VERSION 5.7 ;
  NOWIREEXTENSIONATPIN ON ;
  DIVIDERCHAR "/" ;
  BUSBITCHARS "[]" ;
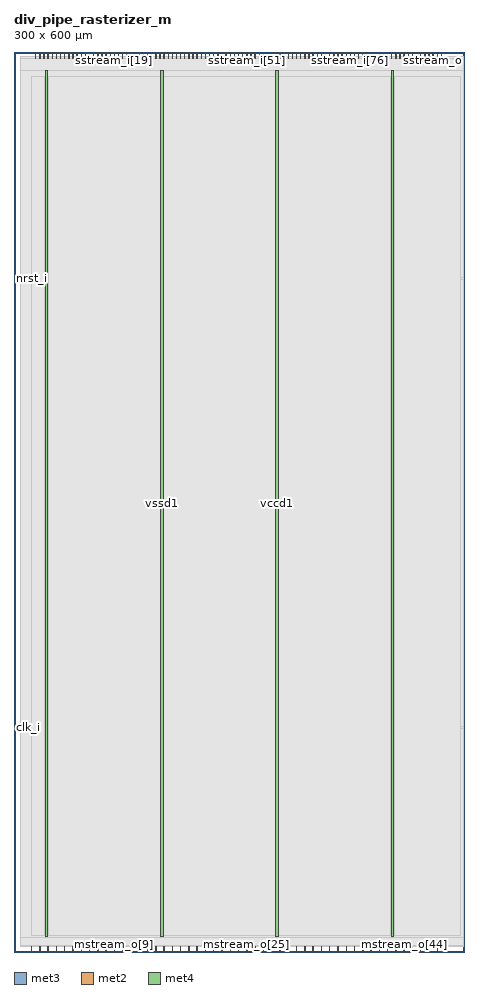
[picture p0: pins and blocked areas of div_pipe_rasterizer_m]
MACRO div_pipe_rasterizer_m
  CLASS BLOCK ;
  FOREIGN div_pipe_rasterizer_m ;
  ORIGIN 0.000 0.000 ;
  SIZE 300.000 BY 600.000 ;
  PIN clk_i
    DIRECTION INPUT ;
    USE SIGNAL ;
    ANTENNAGATEAREA 0.852000 ;
    PORT
      LAYER met3 ;
        RECT 0.000 149.640 4.000 150.240 ;
    END
  END clk_i
  PIN mstream_i
    DIRECTION INPUT ;
    USE SIGNAL ;
    ANTENNAGATEAREA 0.247500 ;
    PORT
      LAYER met2 ;
        RECT 11.590 0.000 11.870 4.000 ;
    END
  END mstream_i
  PIN mstream_o[0]
    DIRECTION OUTPUT TRISTATE ;
    USE SIGNAL ;
    ANTENNADIFFAREA 2.673000 ;
    PORT
      LAYER met2 ;
        RECT 17.110 0.000 17.390 4.000 ;
    END
  END mstream_o[0]
  PIN mstream_o[10]
    DIRECTION OUTPUT TRISTATE ;
    USE SIGNAL ;
    ANTENNADIFFAREA 2.673000 ;
    PORT
      LAYER met2 ;
        RECT 72.310 0.000 72.590 4.000 ;
    END
  END mstream_o[10]
  PIN mstream_o[11]
    DIRECTION OUTPUT TRISTATE ;
    USE SIGNAL ;
    ANTENNADIFFAREA 2.673000 ;
    PORT
      LAYER met2 ;
        RECT 77.830 0.000 78.110 4.000 ;
    END
  END mstream_o[11]
  PIN mstream_o[12]
    DIRECTION OUTPUT TRISTATE ;
    USE SIGNAL ;
    ANTENNADIFFAREA 2.673000 ;
    PORT
      LAYER met2 ;
        RECT 83.350 0.000 83.630 4.000 ;
    END
  END mstream_o[12]
  PIN mstream_o[13]
    DIRECTION OUTPUT TRISTATE ;
    USE SIGNAL ;
    ANTENNADIFFAREA 2.673000 ;
    PORT
      LAYER met2 ;
        RECT 88.870 0.000 89.150 4.000 ;
    END
  END mstream_o[13]
  PIN mstream_o[14]
    DIRECTION OUTPUT TRISTATE ;
    USE SIGNAL ;
    ANTENNADIFFAREA 2.673000 ;
    PORT
      LAYER met2 ;
        RECT 94.390 0.000 94.670 4.000 ;
    END
  END mstream_o[14]
  PIN mstream_o[15]
    DIRECTION OUTPUT TRISTATE ;
    USE SIGNAL ;
    ANTENNADIFFAREA 2.673000 ;
    PORT
      LAYER met2 ;
        RECT 99.910 0.000 100.190 4.000 ;
    END
  END mstream_o[15]
  PIN mstream_o[16]
    DIRECTION OUTPUT TRISTATE ;
    USE SIGNAL ;
    ANTENNADIFFAREA 2.673000 ;
    PORT
      LAYER met2 ;
        RECT 105.430 0.000 105.710 4.000 ;
    END
  END mstream_o[16]
  PIN mstream_o[17]
    DIRECTION OUTPUT TRISTATE ;
    USE SIGNAL ;
    ANTENNADIFFAREA 2.673000 ;
    PORT
      LAYER met2 ;
        RECT 110.950 0.000 111.230 4.000 ;
    END
  END mstream_o[17]
  PIN mstream_o[18]
    DIRECTION OUTPUT TRISTATE ;
    USE SIGNAL ;
    ANTENNADIFFAREA 2.673000 ;
    PORT
      LAYER met2 ;
        RECT 116.470 0.000 116.750 4.000 ;
    END
  END mstream_o[18]
  PIN mstream_o[19]
    DIRECTION OUTPUT TRISTATE ;
    USE SIGNAL ;
    ANTENNADIFFAREA 2.673000 ;
    PORT
      LAYER met2 ;
        RECT 121.990 0.000 122.270 4.000 ;
    END
  END mstream_o[19]
  PIN mstream_o[1]
    DIRECTION OUTPUT TRISTATE ;
    USE SIGNAL ;
    ANTENNADIFFAREA 2.673000 ;
    PORT
      LAYER met2 ;
        RECT 22.630 0.000 22.910 4.000 ;
    END
  END mstream_o[1]
  PIN mstream_o[20]
    DIRECTION OUTPUT TRISTATE ;
    USE SIGNAL ;
    ANTENNADIFFAREA 2.673000 ;
    PORT
      LAYER met2 ;
        RECT 127.510 0.000 127.790 4.000 ;
    END
  END mstream_o[20]
  PIN mstream_o[21]
    DIRECTION OUTPUT TRISTATE ;
    USE SIGNAL ;
    ANTENNADIFFAREA 2.673000 ;
    PORT
      LAYER met2 ;
        RECT 133.030 0.000 133.310 4.000 ;
    END
  END mstream_o[21]
  PIN mstream_o[22]
    DIRECTION OUTPUT TRISTATE ;
    USE SIGNAL ;
    ANTENNADIFFAREA 2.673000 ;
    PORT
      LAYER met2 ;
        RECT 138.550 0.000 138.830 4.000 ;
    END
  END mstream_o[22]
  PIN mstream_o[23]
    DIRECTION OUTPUT TRISTATE ;
    USE SIGNAL ;
    ANTENNADIFFAREA 2.673000 ;
    PORT
      LAYER met2 ;
        RECT 144.070 0.000 144.350 4.000 ;
    END
  END mstream_o[23]
  PIN mstream_o[24]
    DIRECTION OUTPUT TRISTATE ;
    USE SIGNAL ;
    ANTENNADIFFAREA 2.673000 ;
    PORT
      LAYER met2 ;
        RECT 149.590 0.000 149.870 4.000 ;
    END
  END mstream_o[24]
  PIN mstream_o[25]
    DIRECTION OUTPUT TRISTATE ;
    USE SIGNAL ;
    ANTENNADIFFAREA 2.673000 ;
    PORT
      LAYER met2 ;
        RECT 155.110 0.000 155.390 4.000 ;
    END
  END mstream_o[25]
  PIN mstream_o[26]
    DIRECTION OUTPUT TRISTATE ;
    USE SIGNAL ;
    ANTENNADIFFAREA 2.673000 ;
    PORT
      LAYER met2 ;
        RECT 160.630 0.000 160.910 4.000 ;
    END
  END mstream_o[26]
  PIN mstream_o[27]
    DIRECTION OUTPUT TRISTATE ;
    USE SIGNAL ;
    ANTENNADIFFAREA 2.673000 ;
    PORT
      LAYER met2 ;
        RECT 166.150 0.000 166.430 4.000 ;
    END
  END mstream_o[27]
  PIN mstream_o[28]
    DIRECTION OUTPUT TRISTATE ;
    USE SIGNAL ;
    ANTENNADIFFAREA 2.673000 ;
    PORT
      LAYER met2 ;
        RECT 171.670 0.000 171.950 4.000 ;
    END
  END mstream_o[28]
  PIN mstream_o[29]
    DIRECTION OUTPUT TRISTATE ;
    USE SIGNAL ;
    ANTENNADIFFAREA 2.673000 ;
    PORT
      LAYER met2 ;
        RECT 177.190 0.000 177.470 4.000 ;
    END
  END mstream_o[29]
  PIN mstream_o[2]
    DIRECTION OUTPUT TRISTATE ;
    USE SIGNAL ;
    ANTENNADIFFAREA 2.673000 ;
    PORT
      LAYER met2 ;
        RECT 28.150 0.000 28.430 4.000 ;
    END
  END mstream_o[2]
  PIN mstream_o[30]
    DIRECTION OUTPUT TRISTATE ;
    USE SIGNAL ;
    ANTENNADIFFAREA 2.673000 ;
    PORT
      LAYER met2 ;
        RECT 182.710 0.000 182.990 4.000 ;
    END
  END mstream_o[30]
  PIN mstream_o[31]
    DIRECTION OUTPUT TRISTATE ;
    USE SIGNAL ;
    ANTENNADIFFAREA 2.673000 ;
    PORT
      LAYER met2 ;
        RECT 188.230 0.000 188.510 4.000 ;
    END
  END mstream_o[31]
  PIN mstream_o[32]
    DIRECTION OUTPUT TRISTATE ;
    USE SIGNAL ;
    ANTENNADIFFAREA 2.673000 ;
    PORT
      LAYER met2 ;
        RECT 193.750 0.000 194.030 4.000 ;
    END
  END mstream_o[32]
  PIN mstream_o[33]
    DIRECTION OUTPUT TRISTATE ;
    USE SIGNAL ;
    ANTENNADIFFAREA 2.673000 ;
    PORT
      LAYER met2 ;
        RECT 199.270 0.000 199.550 4.000 ;
    END
  END mstream_o[33]
  PIN mstream_o[34]
    DIRECTION OUTPUT TRISTATE ;
    USE SIGNAL ;
    ANTENNADIFFAREA 2.673000 ;
    PORT
      LAYER met2 ;
        RECT 204.790 0.000 205.070 4.000 ;
    END
  END mstream_o[34]
  PIN mstream_o[35]
    DIRECTION OUTPUT TRISTATE ;
    USE SIGNAL ;
    ANTENNADIFFAREA 2.673000 ;
    PORT
      LAYER met2 ;
        RECT 210.310 0.000 210.590 4.000 ;
    END
  END mstream_o[35]
  PIN mstream_o[36]
    DIRECTION OUTPUT TRISTATE ;
    USE SIGNAL ;
    ANTENNADIFFAREA 2.673000 ;
    PORT
      LAYER met2 ;
        RECT 215.830 0.000 216.110 4.000 ;
    END
  END mstream_o[36]
  PIN mstream_o[37]
    DIRECTION OUTPUT TRISTATE ;
    USE SIGNAL ;
    ANTENNADIFFAREA 2.673000 ;
    PORT
      LAYER met2 ;
        RECT 221.350 0.000 221.630 4.000 ;
    END
  END mstream_o[37]
  PIN mstream_o[38]
    DIRECTION OUTPUT TRISTATE ;
    USE SIGNAL ;
    ANTENNADIFFAREA 2.673000 ;
    PORT
      LAYER met2 ;
        RECT 226.870 0.000 227.150 4.000 ;
    END
  END mstream_o[38]
  PIN mstream_o[39]
    DIRECTION OUTPUT TRISTATE ;
    USE SIGNAL ;
    ANTENNADIFFAREA 2.673000 ;
    PORT
      LAYER met2 ;
        RECT 232.390 0.000 232.670 4.000 ;
    END
  END mstream_o[39]
  PIN mstream_o[3]
    DIRECTION OUTPUT TRISTATE ;
    USE SIGNAL ;
    ANTENNADIFFAREA 2.673000 ;
    PORT
      LAYER met2 ;
        RECT 33.670 0.000 33.950 4.000 ;
    END
  END mstream_o[3]
  PIN mstream_o[40]
    DIRECTION OUTPUT TRISTATE ;
    USE SIGNAL ;
    ANTENNADIFFAREA 2.673000 ;
    PORT
      LAYER met2 ;
        RECT 237.910 0.000 238.190 4.000 ;
    END
  END mstream_o[40]
  PIN mstream_o[41]
    DIRECTION OUTPUT TRISTATE ;
    USE SIGNAL ;
    ANTENNADIFFAREA 2.673000 ;
    PORT
      LAYER met2 ;
        RECT 243.430 0.000 243.710 4.000 ;
    END
  END mstream_o[41]
  PIN mstream_o[42]
    DIRECTION OUTPUT TRISTATE ;
    USE SIGNAL ;
    ANTENNADIFFAREA 2.673000 ;
    PORT
      LAYER met2 ;
        RECT 248.950 0.000 249.230 4.000 ;
    END
  END mstream_o[42]
  PIN mstream_o[43]
    DIRECTION OUTPUT TRISTATE ;
    USE SIGNAL ;
    ANTENNADIFFAREA 2.673000 ;
    PORT
      LAYER met2 ;
        RECT 254.470 0.000 254.750 4.000 ;
    END
  END mstream_o[43]
  PIN mstream_o[44]
    DIRECTION OUTPUT TRISTATE ;
    USE SIGNAL ;
    ANTENNADIFFAREA 2.673000 ;
    PORT
      LAYER met2 ;
        RECT 259.990 0.000 260.270 4.000 ;
    END
  END mstream_o[44]
  PIN mstream_o[45]
    DIRECTION OUTPUT TRISTATE ;
    USE SIGNAL ;
    ANTENNADIFFAREA 2.673000 ;
    PORT
      LAYER met2 ;
        RECT 265.510 0.000 265.790 4.000 ;
    END
  END mstream_o[45]
  PIN mstream_o[46]
    DIRECTION OUTPUT TRISTATE ;
    USE SIGNAL ;
    ANTENNADIFFAREA 2.673000 ;
    PORT
      LAYER met2 ;
        RECT 271.030 0.000 271.310 4.000 ;
    END
  END mstream_o[46]
  PIN mstream_o[47]
    DIRECTION OUTPUT TRISTATE ;
    USE SIGNAL ;
    ANTENNADIFFAREA 2.673000 ;
    PORT
      LAYER met2 ;
        RECT 276.550 0.000 276.830 4.000 ;
    END
  END mstream_o[47]
  PIN mstream_o[48]
    DIRECTION OUTPUT TRISTATE ;
    USE SIGNAL ;
    ANTENNADIFFAREA 2.673000 ;
    PORT
      LAYER met2 ;
        RECT 282.070 0.000 282.350 4.000 ;
    END
  END mstream_o[48]
  PIN mstream_o[49]
    DIRECTION OUTPUT TRISTATE ;
    USE SIGNAL ;
    PORT
      LAYER met2 ;
        RECT 287.590 0.000 287.870 4.000 ;
    END
  END mstream_o[49]
  PIN mstream_o[4]
    DIRECTION OUTPUT TRISTATE ;
    USE SIGNAL ;
    ANTENNADIFFAREA 2.673000 ;
    PORT
      LAYER met2 ;
        RECT 39.190 0.000 39.470 4.000 ;
    END
  END mstream_o[4]
  PIN mstream_o[5]
    DIRECTION OUTPUT TRISTATE ;
    USE SIGNAL ;
    ANTENNADIFFAREA 2.673000 ;
    PORT
      LAYER met2 ;
        RECT 44.710 0.000 44.990 4.000 ;
    END
  END mstream_o[5]
  PIN mstream_o[6]
    DIRECTION OUTPUT TRISTATE ;
    USE SIGNAL ;
    ANTENNADIFFAREA 2.673000 ;
    PORT
      LAYER met2 ;
        RECT 50.230 0.000 50.510 4.000 ;
    END
  END mstream_o[6]
  PIN mstream_o[7]
    DIRECTION OUTPUT TRISTATE ;
    USE SIGNAL ;
    ANTENNADIFFAREA 2.673000 ;
    PORT
      LAYER met2 ;
        RECT 55.750 0.000 56.030 4.000 ;
    END
  END mstream_o[7]
  PIN mstream_o[8]
    DIRECTION OUTPUT TRISTATE ;
    USE SIGNAL ;
    ANTENNADIFFAREA 2.673000 ;
    PORT
      LAYER met2 ;
        RECT 61.270 0.000 61.550 4.000 ;
    END
  END mstream_o[8]
  PIN mstream_o[9]
    DIRECTION OUTPUT TRISTATE ;
    USE SIGNAL ;
    ANTENNADIFFAREA 2.673000 ;
    PORT
      LAYER met2 ;
        RECT 66.790 0.000 67.070 4.000 ;
    END
  END mstream_o[9]
  PIN nrst_i
    DIRECTION INPUT ;
    USE SIGNAL ;
    ANTENNAGATEAREA 0.247500 ;
    PORT
      LAYER met3 ;
        RECT 0.000 448.840 4.000 449.440 ;
    END
  END nrst_i
  PIN sstream_i[0]
    DIRECTION INPUT ;
    USE SIGNAL ;
    ANTENNAGATEAREA 0.159000 ;
    PORT
      LAYER met2 ;
        RECT 14.350 596.000 14.630 600.000 ;
    END
  END sstream_i[0]
  PIN sstream_i[10]
    DIRECTION INPUT ;
    USE SIGNAL ;
    ANTENNAGATEAREA 0.426000 ;
    PORT
      LAYER met2 ;
        RECT 41.950 596.000 42.230 600.000 ;
    END
  END sstream_i[10]
  PIN sstream_i[11]
    DIRECTION INPUT ;
    USE SIGNAL ;
    ANTENNAGATEAREA 0.213000 ;
    PORT
      LAYER met2 ;
        RECT 44.710 596.000 44.990 600.000 ;
    END
  END sstream_i[11]
  PIN sstream_i[12]
    DIRECTION INPUT ;
    USE SIGNAL ;
    ANTENNAGATEAREA 0.159000 ;
    PORT
      LAYER met2 ;
        RECT 47.470 596.000 47.750 600.000 ;
    END
  END sstream_i[12]
  PIN sstream_i[13]
    DIRECTION INPUT ;
    USE SIGNAL ;
    ANTENNAGATEAREA 0.213000 ;
    PORT
      LAYER met2 ;
        RECT 50.230 596.000 50.510 600.000 ;
    END
  END sstream_i[13]
  PIN sstream_i[14]
    DIRECTION INPUT ;
    USE SIGNAL ;
    ANTENNAGATEAREA 0.213000 ;
    PORT
      LAYER met2 ;
        RECT 52.990 596.000 53.270 600.000 ;
    END
  END sstream_i[14]
  PIN sstream_i[15]
    DIRECTION INPUT ;
    USE SIGNAL ;
    ANTENNAGATEAREA 0.213000 ;
    PORT
      LAYER met2 ;
        RECT 55.750 596.000 56.030 600.000 ;
    END
  END sstream_i[15]
  PIN sstream_i[16]
    DIRECTION INPUT ;
    USE SIGNAL ;
    ANTENNAGATEAREA 0.213000 ;
    PORT
      LAYER met2 ;
        RECT 58.510 596.000 58.790 600.000 ;
    END
  END sstream_i[16]
  PIN sstream_i[17]
    DIRECTION INPUT ;
    USE SIGNAL ;
    ANTENNAGATEAREA 0.213000 ;
    PORT
      LAYER met2 ;
        RECT 61.270 596.000 61.550 600.000 ;
    END
  END sstream_i[17]
  PIN sstream_i[18]
    DIRECTION INPUT ;
    USE SIGNAL ;
    ANTENNAGATEAREA 0.213000 ;
    PORT
      LAYER met2 ;
        RECT 64.030 596.000 64.310 600.000 ;
    END
  END sstream_i[18]
  PIN sstream_i[19]
    DIRECTION INPUT ;
    USE SIGNAL ;
    ANTENNAGATEAREA 0.213000 ;
    PORT
      LAYER met2 ;
        RECT 66.790 596.000 67.070 600.000 ;
    END
  END sstream_i[19]
  PIN sstream_i[1]
    DIRECTION INPUT ;
    USE SIGNAL ;
    ANTENNAGATEAREA 0.247500 ;
    PORT
      LAYER met2 ;
        RECT 17.110 596.000 17.390 600.000 ;
    END
  END sstream_i[1]
  PIN sstream_i[20]
    DIRECTION INPUT ;
    USE SIGNAL ;
    ANTENNAGATEAREA 0.213000 ;
    PORT
      LAYER met2 ;
        RECT 69.550 596.000 69.830 600.000 ;
    END
  END sstream_i[20]
  PIN sstream_i[21]
    DIRECTION INPUT ;
    USE SIGNAL ;
    ANTENNAGATEAREA 0.213000 ;
    PORT
      LAYER met2 ;
        RECT 72.310 596.000 72.590 600.000 ;
    END
  END sstream_i[21]
  PIN sstream_i[22]
    DIRECTION INPUT ;
    USE SIGNAL ;
    ANTENNAGATEAREA 0.213000 ;
    PORT
      LAYER met2 ;
        RECT 75.070 596.000 75.350 600.000 ;
    END
  END sstream_i[22]
  PIN sstream_i[23]
    DIRECTION INPUT ;
    USE SIGNAL ;
    ANTENNAGATEAREA 0.213000 ;
    PORT
      LAYER met2 ;
        RECT 77.830 596.000 78.110 600.000 ;
    END
  END sstream_i[23]
  PIN sstream_i[24]
    DIRECTION INPUT ;
    USE SIGNAL ;
    ANTENNAGATEAREA 0.126000 ;
    PORT
      LAYER met2 ;
        RECT 80.590 596.000 80.870 600.000 ;
    END
  END sstream_i[24]
  PIN sstream_i[25]
    DIRECTION INPUT ;
    USE SIGNAL ;
    ANTENNAGATEAREA 0.196500 ;
    PORT
      LAYER met2 ;
        RECT 83.350 596.000 83.630 600.000 ;
    END
  END sstream_i[25]
  PIN sstream_i[26]
    DIRECTION INPUT ;
    USE SIGNAL ;
    ANTENNAGATEAREA 0.213000 ;
    PORT
      LAYER met2 ;
        RECT 86.110 596.000 86.390 600.000 ;
    END
  END sstream_i[26]
  PIN sstream_i[27]
    DIRECTION INPUT ;
    USE SIGNAL ;
    ANTENNAGATEAREA 0.213000 ;
    PORT
      LAYER met2 ;
        RECT 88.870 596.000 89.150 600.000 ;
    END
  END sstream_i[27]
  PIN sstream_i[28]
    DIRECTION INPUT ;
    USE SIGNAL ;
    ANTENNAGATEAREA 0.196500 ;
    PORT
      LAYER met2 ;
        RECT 91.630 596.000 91.910 600.000 ;
    END
  END sstream_i[28]
  PIN sstream_i[29]
    DIRECTION INPUT ;
    USE SIGNAL ;
    ANTENNAGATEAREA 0.213000 ;
    PORT
      LAYER met2 ;
        RECT 94.390 596.000 94.670 600.000 ;
    END
  END sstream_i[29]
  PIN sstream_i[2]
    DIRECTION INPUT ;
    USE SIGNAL ;
    ANTENNAGATEAREA 0.247500 ;
    PORT
      LAYER met2 ;
        RECT 19.870 596.000 20.150 600.000 ;
    END
  END sstream_i[2]
  PIN sstream_i[30]
    DIRECTION INPUT ;
    USE SIGNAL ;
    ANTENNAGATEAREA 0.213000 ;
    PORT
      LAYER met2 ;
        RECT 97.150 596.000 97.430 600.000 ;
    END
  END sstream_i[30]
  PIN sstream_i[31]
    DIRECTION INPUT ;
    USE SIGNAL ;
    ANTENNAGATEAREA 0.196500 ;
    PORT
      LAYER met2 ;
        RECT 99.910 596.000 100.190 600.000 ;
    END
  END sstream_i[31]
  PIN sstream_i[32]
    DIRECTION INPUT ;
    USE SIGNAL ;
    ANTENNAGATEAREA 0.213000 ;
    PORT
      LAYER met2 ;
        RECT 102.670 596.000 102.950 600.000 ;
    END
  END sstream_i[32]
  PIN sstream_i[33]
    DIRECTION INPUT ;
    USE SIGNAL ;
    ANTENNAGATEAREA 0.126000 ;
    PORT
      LAYER met2 ;
        RECT 105.430 596.000 105.710 600.000 ;
    END
  END sstream_i[33]
  PIN sstream_i[34]
    DIRECTION INPUT ;
    USE SIGNAL ;
    ANTENNAGATEAREA 0.196500 ;
    PORT
      LAYER met2 ;
        RECT 108.190 596.000 108.470 600.000 ;
    END
  END sstream_i[34]
  PIN sstream_i[35]
    DIRECTION INPUT ;
    USE SIGNAL ;
    ANTENNAGATEAREA 0.213000 ;
    PORT
      LAYER met2 ;
        RECT 110.950 596.000 111.230 600.000 ;
    END
  END sstream_i[35]
  PIN sstream_i[36]
    DIRECTION INPUT ;
    USE SIGNAL ;
    ANTENNAGATEAREA 0.126000 ;
    PORT
      LAYER met2 ;
        RECT 113.710 596.000 113.990 600.000 ;
    END
  END sstream_i[36]
  PIN sstream_i[37]
    DIRECTION INPUT ;
    USE SIGNAL ;
    ANTENNAGATEAREA 0.126000 ;
    PORT
      LAYER met2 ;
        RECT 116.470 596.000 116.750 600.000 ;
    END
  END sstream_i[37]
  PIN sstream_i[38]
    DIRECTION INPUT ;
    USE SIGNAL ;
    ANTENNAGATEAREA 0.213000 ;
    PORT
      LAYER met2 ;
        RECT 119.230 596.000 119.510 600.000 ;
    END
  END sstream_i[38]
  PIN sstream_i[39]
    DIRECTION INPUT ;
    USE SIGNAL ;
    ANTENNAGATEAREA 0.126000 ;
    PORT
      LAYER met2 ;
        RECT 121.990 596.000 122.270 600.000 ;
    END
  END sstream_i[39]
  PIN sstream_i[3]
    DIRECTION INPUT ;
    USE SIGNAL ;
    ANTENNAGATEAREA 0.213000 ;
    PORT
      LAYER met2 ;
        RECT 22.630 596.000 22.910 600.000 ;
    END
  END sstream_i[3]
  PIN sstream_i[40]
    DIRECTION INPUT ;
    USE SIGNAL ;
    ANTENNAGATEAREA 0.196500 ;
    PORT
      LAYER met2 ;
        RECT 124.750 596.000 125.030 600.000 ;
    END
  END sstream_i[40]
  PIN sstream_i[41]
    DIRECTION INPUT ;
    USE SIGNAL ;
    ANTENNAGATEAREA 0.126000 ;
    PORT
      LAYER met2 ;
        RECT 127.510 596.000 127.790 600.000 ;
    END
  END sstream_i[41]
  PIN sstream_i[42]
    DIRECTION INPUT ;
    USE SIGNAL ;
    ANTENNAGATEAREA 0.196500 ;
    PORT
      LAYER met2 ;
        RECT 130.270 596.000 130.550 600.000 ;
    END
  END sstream_i[42]
  PIN sstream_i[43]
    DIRECTION INPUT ;
    USE SIGNAL ;
    ANTENNAGATEAREA 0.196500 ;
    PORT
      LAYER met2 ;
        RECT 133.030 596.000 133.310 600.000 ;
    END
  END sstream_i[43]
  PIN sstream_i[44]
    DIRECTION INPUT ;
    USE SIGNAL ;
    ANTENNAGATEAREA 0.126000 ;
    PORT
      LAYER met2 ;
        RECT 135.790 596.000 136.070 600.000 ;
    END
  END sstream_i[44]
  PIN sstream_i[45]
    DIRECTION INPUT ;
    USE SIGNAL ;
    ANTENNAGATEAREA 0.196500 ;
    PORT
      LAYER met2 ;
        RECT 138.550 596.000 138.830 600.000 ;
    END
  END sstream_i[45]
  PIN sstream_i[46]
    DIRECTION INPUT ;
    USE SIGNAL ;
    ANTENNAGATEAREA 0.196500 ;
    PORT
      LAYER met2 ;
        RECT 141.310 596.000 141.590 600.000 ;
    END
  END sstream_i[46]
  PIN sstream_i[47]
    DIRECTION INPUT ;
    USE SIGNAL ;
    ANTENNAGATEAREA 0.196500 ;
    PORT
      LAYER met2 ;
        RECT 144.070 596.000 144.350 600.000 ;
    END
  END sstream_i[47]
  PIN sstream_i[48]
    DIRECTION INPUT ;
    USE SIGNAL ;
    ANTENNAGATEAREA 0.126000 ;
    PORT
      LAYER met2 ;
        RECT 146.830 596.000 147.110 600.000 ;
    END
  END sstream_i[48]
  PIN sstream_i[49]
    DIRECTION INPUT ;
    USE SIGNAL ;
    ANTENNAGATEAREA 0.196500 ;
    PORT
      LAYER met2 ;
        RECT 149.590 596.000 149.870 600.000 ;
    END
  END sstream_i[49]
  PIN sstream_i[4]
    DIRECTION INPUT ;
    USE SIGNAL ;
    ANTENNAGATEAREA 0.247500 ;
    PORT
      LAYER met2 ;
        RECT 25.390 596.000 25.670 600.000 ;
    END
  END sstream_i[4]
  PIN sstream_i[50]
    DIRECTION INPUT ;
    USE SIGNAL ;
    ANTENNAGATEAREA 0.196500 ;
    PORT
      LAYER met2 ;
        RECT 152.350 596.000 152.630 600.000 ;
    END
  END sstream_i[50]
  PIN sstream_i[51]
    DIRECTION INPUT ;
    USE SIGNAL ;
    ANTENNAGATEAREA 0.196500 ;
    PORT
      LAYER met2 ;
        RECT 155.110 596.000 155.390 600.000 ;
    END
  END sstream_i[51]
  PIN sstream_i[52]
    DIRECTION INPUT ;
    USE SIGNAL ;
    ANTENNAGATEAREA 0.196500 ;
    PORT
      LAYER met2 ;
        RECT 157.870 596.000 158.150 600.000 ;
    END
  END sstream_i[52]
  PIN sstream_i[53]
    DIRECTION INPUT ;
    USE SIGNAL ;
    ANTENNAGATEAREA 0.196500 ;
    PORT
      LAYER met2 ;
        RECT 160.630 596.000 160.910 600.000 ;
    END
  END sstream_i[53]
  PIN sstream_i[54]
    DIRECTION INPUT ;
    USE SIGNAL ;
    ANTENNAGATEAREA 0.196500 ;
    PORT
      LAYER met2 ;
        RECT 163.390 596.000 163.670 600.000 ;
    END
  END sstream_i[54]
  PIN sstream_i[55]
    DIRECTION INPUT ;
    USE SIGNAL ;
    ANTENNAGATEAREA 0.196500 ;
    PORT
      LAYER met2 ;
        RECT 166.150 596.000 166.430 600.000 ;
    END
  END sstream_i[55]
  PIN sstream_i[56]
    DIRECTION INPUT ;
    USE SIGNAL ;
    ANTENNAGATEAREA 0.196500 ;
    PORT
      LAYER met2 ;
        RECT 168.910 596.000 169.190 600.000 ;
    END
  END sstream_i[56]
  PIN sstream_i[57]
    DIRECTION INPUT ;
    USE SIGNAL ;
    ANTENNAGATEAREA 0.196500 ;
    PORT
      LAYER met2 ;
        RECT 171.670 596.000 171.950 600.000 ;
    END
  END sstream_i[57]
  PIN sstream_i[58]
    DIRECTION INPUT ;
    USE SIGNAL ;
    ANTENNAGATEAREA 0.196500 ;
    PORT
      LAYER met2 ;
        RECT 174.430 596.000 174.710 600.000 ;
    END
  END sstream_i[58]
  PIN sstream_i[59]
    DIRECTION INPUT ;
    USE SIGNAL ;
    ANTENNAGATEAREA 0.196500 ;
    PORT
      LAYER met2 ;
        RECT 177.190 596.000 177.470 600.000 ;
    END
  END sstream_i[59]
  PIN sstream_i[5]
    DIRECTION INPUT ;
    USE SIGNAL ;
    ANTENNAGATEAREA 0.159000 ;
    PORT
      LAYER met2 ;
        RECT 28.150 596.000 28.430 600.000 ;
    END
  END sstream_i[5]
  PIN sstream_i[60]
    DIRECTION INPUT ;
    USE SIGNAL ;
    ANTENNAGATEAREA 0.196500 ;
    PORT
      LAYER met2 ;
        RECT 179.950 596.000 180.230 600.000 ;
    END
  END sstream_i[60]
  PIN sstream_i[61]
    DIRECTION INPUT ;
    USE SIGNAL ;
    ANTENNAGATEAREA 0.196500 ;
    PORT
      LAYER met2 ;
        RECT 182.710 596.000 182.990 600.000 ;
    END
  END sstream_i[61]
  PIN sstream_i[62]
    DIRECTION INPUT ;
    USE SIGNAL ;
    ANTENNAGATEAREA 0.196500 ;
    PORT
      LAYER met2 ;
        RECT 185.470 596.000 185.750 600.000 ;
    END
  END sstream_i[62]
  PIN sstream_i[63]
    DIRECTION INPUT ;
    USE SIGNAL ;
    ANTENNAGATEAREA 0.196500 ;
    PORT
      LAYER met2 ;
        RECT 188.230 596.000 188.510 600.000 ;
    END
  END sstream_i[63]
  PIN sstream_i[64]
    DIRECTION INPUT ;
    USE SIGNAL ;
    ANTENNAGATEAREA 0.196500 ;
    PORT
      LAYER met2 ;
        RECT 190.990 596.000 191.270 600.000 ;
    END
  END sstream_i[64]
  PIN sstream_i[65]
    DIRECTION INPUT ;
    USE SIGNAL ;
    ANTENNAGATEAREA 0.126000 ;
    PORT
      LAYER met2 ;
        RECT 193.750 596.000 194.030 600.000 ;
    END
  END sstream_i[65]
  PIN sstream_i[66]
    DIRECTION INPUT ;
    USE SIGNAL ;
    ANTENNAGATEAREA 0.213000 ;
    PORT
      LAYER met2 ;
        RECT 196.510 596.000 196.790 600.000 ;
    END
  END sstream_i[66]
  PIN sstream_i[67]
    DIRECTION INPUT ;
    USE SIGNAL ;
    ANTENNAGATEAREA 0.213000 ;
    PORT
      LAYER met2 ;
        RECT 199.270 596.000 199.550 600.000 ;
    END
  END sstream_i[67]
  PIN sstream_i[68]
    DIRECTION INPUT ;
    USE SIGNAL ;
    ANTENNAGATEAREA 0.196500 ;
    PORT
      LAYER met2 ;
        RECT 202.030 596.000 202.310 600.000 ;
    END
  END sstream_i[68]
  PIN sstream_i[69]
    DIRECTION INPUT ;
    USE SIGNAL ;
    ANTENNAGATEAREA 0.196500 ;
    PORT
      LAYER met2 ;
        RECT 204.790 596.000 205.070 600.000 ;
    END
  END sstream_i[69]
  PIN sstream_i[6]
    DIRECTION INPUT ;
    USE SIGNAL ;
    ANTENNAGATEAREA 0.159000 ;
    PORT
      LAYER met2 ;
        RECT 30.910 596.000 31.190 600.000 ;
    END
  END sstream_i[6]
  PIN sstream_i[70]
    DIRECTION INPUT ;
    USE SIGNAL ;
    ANTENNAGATEAREA 0.196500 ;
    PORT
      LAYER met2 ;
        RECT 207.550 596.000 207.830 600.000 ;
    END
  END sstream_i[70]
  PIN sstream_i[71]
    DIRECTION INPUT ;
    USE SIGNAL ;
    ANTENNAGATEAREA 0.196500 ;
    PORT
      LAYER met2 ;
        RECT 210.310 596.000 210.590 600.000 ;
    END
  END sstream_i[71]
  PIN sstream_i[72]
    DIRECTION INPUT ;
    USE SIGNAL ;
    ANTENNAGATEAREA 0.196500 ;
    PORT
      LAYER met2 ;
        RECT 213.070 596.000 213.350 600.000 ;
    END
  END sstream_i[72]
  PIN sstream_i[73]
    DIRECTION INPUT ;
    USE SIGNAL ;
    ANTENNAGATEAREA 0.196500 ;
    PORT
      LAYER met2 ;
        RECT 215.830 596.000 216.110 600.000 ;
    END
  END sstream_i[73]
  PIN sstream_i[74]
    DIRECTION INPUT ;
    USE SIGNAL ;
    ANTENNAGATEAREA 0.196500 ;
    PORT
      LAYER met2 ;
        RECT 218.590 596.000 218.870 600.000 ;
    END
  END sstream_i[74]
  PIN sstream_i[75]
    DIRECTION INPUT ;
    USE SIGNAL ;
    ANTENNAGATEAREA 0.196500 ;
    PORT
      LAYER met2 ;
        RECT 221.350 596.000 221.630 600.000 ;
    END
  END sstream_i[75]
  PIN sstream_i[76]
    DIRECTION INPUT ;
    USE SIGNAL ;
    ANTENNAGATEAREA 0.196500 ;
    PORT
      LAYER met2 ;
        RECT 224.110 596.000 224.390 600.000 ;
    END
  END sstream_i[76]
  PIN sstream_i[77]
    DIRECTION INPUT ;
    USE SIGNAL ;
    ANTENNAGATEAREA 0.196500 ;
    PORT
      LAYER met2 ;
        RECT 226.870 596.000 227.150 600.000 ;
    END
  END sstream_i[77]
  PIN sstream_i[78]
    DIRECTION INPUT ;
    USE SIGNAL ;
    ANTENNAGATEAREA 0.196500 ;
    PORT
      LAYER met2 ;
        RECT 229.630 596.000 229.910 600.000 ;
    END
  END sstream_i[78]
  PIN sstream_i[79]
    DIRECTION INPUT ;
    USE SIGNAL ;
    ANTENNAGATEAREA 0.196500 ;
    PORT
      LAYER met2 ;
        RECT 232.390 596.000 232.670 600.000 ;
    END
  END sstream_i[79]
  PIN sstream_i[7]
    DIRECTION INPUT ;
    USE SIGNAL ;
    ANTENNAGATEAREA 0.247500 ;
    PORT
      LAYER met2 ;
        RECT 33.670 596.000 33.950 600.000 ;
    END
  END sstream_i[7]
  PIN sstream_i[80]
    DIRECTION INPUT ;
    USE SIGNAL ;
    ANTENNAGATEAREA 0.196500 ;
    PORT
      LAYER met2 ;
        RECT 235.150 596.000 235.430 600.000 ;
    END
  END sstream_i[80]
  PIN sstream_i[81]
    DIRECTION INPUT ;
    USE SIGNAL ;
    ANTENNAGATEAREA 0.196500 ;
    PORT
      LAYER met2 ;
        RECT 237.910 596.000 238.190 600.000 ;
    END
  END sstream_i[81]
  PIN sstream_i[82]
    DIRECTION INPUT ;
    USE SIGNAL ;
    ANTENNAGATEAREA 0.196500 ;
    PORT
      LAYER met2 ;
        RECT 240.670 596.000 240.950 600.000 ;
    END
  END sstream_i[82]
  PIN sstream_i[83]
    DIRECTION INPUT ;
    USE SIGNAL ;
    ANTENNAGATEAREA 0.213000 ;
    PORT
      LAYER met2 ;
        RECT 243.430 596.000 243.710 600.000 ;
    END
  END sstream_i[83]
  PIN sstream_i[84]
    DIRECTION INPUT ;
    USE SIGNAL ;
    ANTENNAGATEAREA 0.196500 ;
    PORT
      LAYER met2 ;
        RECT 246.190 596.000 246.470 600.000 ;
    END
  END sstream_i[84]
  PIN sstream_i[85]
    DIRECTION INPUT ;
    USE SIGNAL ;
    ANTENNAGATEAREA 0.196500 ;
    PORT
      LAYER met2 ;
        RECT 248.950 596.000 249.230 600.000 ;
    END
  END sstream_i[85]
  PIN sstream_i[86]
    DIRECTION INPUT ;
    USE SIGNAL ;
    ANTENNAGATEAREA 0.159000 ;
    PORT
      LAYER met2 ;
        RECT 251.710 596.000 251.990 600.000 ;
    END
  END sstream_i[86]
  PIN sstream_i[87]
    DIRECTION INPUT ;
    USE SIGNAL ;
    ANTENNAGATEAREA 0.126000 ;
    PORT
      LAYER met2 ;
        RECT 254.470 596.000 254.750 600.000 ;
    END
  END sstream_i[87]
  PIN sstream_i[88]
    DIRECTION INPUT ;
    USE SIGNAL ;
    ANTENNAGATEAREA 0.213000 ;
    PORT
      LAYER met2 ;
        RECT 257.230 596.000 257.510 600.000 ;
    END
  END sstream_i[88]
  PIN sstream_i[89]
    DIRECTION INPUT ;
    USE SIGNAL ;
    ANTENNAGATEAREA 0.196500 ;
    PORT
      LAYER met2 ;
        RECT 259.990 596.000 260.270 600.000 ;
    END
  END sstream_i[89]
  PIN sstream_i[8]
    DIRECTION INPUT ;
    USE SIGNAL ;
    ANTENNAGATEAREA 0.213000 ;
    PORT
      LAYER met2 ;
        RECT 36.430 596.000 36.710 600.000 ;
    END
  END sstream_i[8]
  PIN sstream_i[90]
    DIRECTION INPUT ;
    USE SIGNAL ;
    ANTENNAGATEAREA 0.126000 ;
    PORT
      LAYER met2 ;
        RECT 262.750 596.000 263.030 600.000 ;
    END
  END sstream_i[90]
  PIN sstream_i[91]
    DIRECTION INPUT ;
    USE SIGNAL ;
    ANTENNAGATEAREA 0.196500 ;
    PORT
      LAYER met2 ;
        RECT 265.510 596.000 265.790 600.000 ;
    END
  END sstream_i[91]
  PIN sstream_i[92]
    DIRECTION INPUT ;
    USE SIGNAL ;
    ANTENNAGATEAREA 0.126000 ;
    PORT
      LAYER met2 ;
        RECT 268.270 596.000 268.550 600.000 ;
    END
  END sstream_i[92]
  PIN sstream_i[93]
    DIRECTION INPUT ;
    USE SIGNAL ;
    ANTENNAGATEAREA 0.126000 ;
    PORT
      LAYER met2 ;
        RECT 271.030 596.000 271.310 600.000 ;
    END
  END sstream_i[93]
  PIN sstream_i[94]
    DIRECTION INPUT ;
    USE SIGNAL ;
    ANTENNAGATEAREA 0.196500 ;
    PORT
      LAYER met2 ;
        RECT 273.790 596.000 274.070 600.000 ;
    END
  END sstream_i[94]
  PIN sstream_i[95]
    DIRECTION INPUT ;
    USE SIGNAL ;
    ANTENNAGATEAREA 0.196500 ;
    PORT
      LAYER met2 ;
        RECT 276.550 596.000 276.830 600.000 ;
    END
  END sstream_i[95]
  PIN sstream_i[96]
    DIRECTION INPUT ;
    USE SIGNAL ;
    ANTENNAGATEAREA 0.196500 ;
    PORT
      LAYER met2 ;
        RECT 279.310 596.000 279.590 600.000 ;
    END
  END sstream_i[96]
  PIN sstream_i[97]
    DIRECTION INPUT ;
    USE SIGNAL ;
    PORT
      LAYER met2 ;
        RECT 282.070 596.000 282.350 600.000 ;
    END
  END sstream_i[97]
  PIN sstream_i[9]
    DIRECTION INPUT ;
    USE SIGNAL ;
    ANTENNAGATEAREA 0.213000 ;
    PORT
      LAYER met2 ;
        RECT 39.190 596.000 39.470 600.000 ;
    END
  END sstream_i[9]
  PIN sstream_o
    DIRECTION OUTPUT TRISTATE ;
    USE SIGNAL ;
    ANTENNADIFFAREA 2.673000 ;
    PORT
      LAYER met2 ;
        RECT 284.830 596.000 285.110 600.000 ;
    END
  END sstream_o
  PIN vccd1
    DIRECTION INOUT ;
    USE POWER ;
    PORT
      LAYER met4 ;
        RECT 21.040 10.640 22.640 587.760 ;
    END
    PORT
      LAYER met4 ;
        RECT 174.640 10.640 176.240 587.760 ;
    END
  END vccd1
  PIN vssd1
    DIRECTION INOUT ;
    USE GROUND ;
    PORT
      LAYER met4 ;
        RECT 97.840 10.640 99.440 587.760 ;
    END
    PORT
      LAYER met4 ;
        RECT 251.440 10.640 253.040 587.760 ;
    END
  END vssd1
  OBS
      LAYER li1 ;
        RECT 5.520 10.795 294.400 587.605 ;
      LAYER met1 ;
        RECT 4.210 8.200 299.850 590.880 ;
      LAYER met2 ;
        RECT 4.230 595.720 14.070 596.770 ;
        RECT 14.910 595.720 16.830 596.770 ;
        RECT 17.670 595.720 19.590 596.770 ;
        RECT 20.430 595.720 22.350 596.770 ;
        RECT 23.190 595.720 25.110 596.770 ;
        RECT 25.950 595.720 27.870 596.770 ;
        RECT 28.710 595.720 30.630 596.770 ;
        RECT 31.470 595.720 33.390 596.770 ;
        RECT 34.230 595.720 36.150 596.770 ;
        RECT 36.990 595.720 38.910 596.770 ;
        RECT 39.750 595.720 41.670 596.770 ;
        RECT 42.510 595.720 44.430 596.770 ;
        RECT 45.270 595.720 47.190 596.770 ;
        RECT 48.030 595.720 49.950 596.770 ;
        RECT 50.790 595.720 52.710 596.770 ;
        RECT 53.550 595.720 55.470 596.770 ;
        RECT 56.310 595.720 58.230 596.770 ;
        RECT 59.070 595.720 60.990 596.770 ;
        RECT 61.830 595.720 63.750 596.770 ;
        RECT 64.590 595.720 66.510 596.770 ;
        RECT 67.350 595.720 69.270 596.770 ;
        RECT 70.110 595.720 72.030 596.770 ;
        RECT 72.870 595.720 74.790 596.770 ;
        RECT 75.630 595.720 77.550 596.770 ;
        RECT 78.390 595.720 80.310 596.770 ;
        RECT 81.150 595.720 83.070 596.770 ;
        RECT 83.910 595.720 85.830 596.770 ;
        RECT 86.670 595.720 88.590 596.770 ;
        RECT 89.430 595.720 91.350 596.770 ;
        RECT 92.190 595.720 94.110 596.770 ;
        RECT 94.950 595.720 96.870 596.770 ;
        RECT 97.710 595.720 99.630 596.770 ;
        RECT 100.470 595.720 102.390 596.770 ;
        RECT 103.230 595.720 105.150 596.770 ;
        RECT 105.990 595.720 107.910 596.770 ;
        RECT 108.750 595.720 110.670 596.770 ;
        RECT 111.510 595.720 113.430 596.770 ;
        RECT 114.270 595.720 116.190 596.770 ;
        RECT 117.030 595.720 118.950 596.770 ;
        RECT 119.790 595.720 121.710 596.770 ;
        RECT 122.550 595.720 124.470 596.770 ;
        RECT 125.310 595.720 127.230 596.770 ;
        RECT 128.070 595.720 129.990 596.770 ;
        RECT 130.830 595.720 132.750 596.770 ;
        RECT 133.590 595.720 135.510 596.770 ;
        RECT 136.350 595.720 138.270 596.770 ;
        RECT 139.110 595.720 141.030 596.770 ;
        RECT 141.870 595.720 143.790 596.770 ;
        RECT 144.630 595.720 146.550 596.770 ;
        RECT 147.390 595.720 149.310 596.770 ;
        RECT 150.150 595.720 152.070 596.770 ;
        RECT 152.910 595.720 154.830 596.770 ;
        RECT 155.670 595.720 157.590 596.770 ;
        RECT 158.430 595.720 160.350 596.770 ;
        RECT 161.190 595.720 163.110 596.770 ;
        RECT 163.950 595.720 165.870 596.770 ;
        RECT 166.710 595.720 168.630 596.770 ;
        RECT 169.470 595.720 171.390 596.770 ;
        RECT 172.230 595.720 174.150 596.770 ;
        RECT 174.990 595.720 176.910 596.770 ;
        RECT 177.750 595.720 179.670 596.770 ;
        RECT 180.510 595.720 182.430 596.770 ;
        RECT 183.270 595.720 185.190 596.770 ;
        RECT 186.030 595.720 187.950 596.770 ;
        RECT 188.790 595.720 190.710 596.770 ;
        RECT 191.550 595.720 193.470 596.770 ;
        RECT 194.310 595.720 196.230 596.770 ;
        RECT 197.070 595.720 198.990 596.770 ;
        RECT 199.830 595.720 201.750 596.770 ;
        RECT 202.590 595.720 204.510 596.770 ;
        RECT 205.350 595.720 207.270 596.770 ;
        RECT 208.110 595.720 210.030 596.770 ;
        RECT 210.870 595.720 212.790 596.770 ;
        RECT 213.630 595.720 215.550 596.770 ;
        RECT 216.390 595.720 218.310 596.770 ;
        RECT 219.150 595.720 221.070 596.770 ;
        RECT 221.910 595.720 223.830 596.770 ;
        RECT 224.670 595.720 226.590 596.770 ;
        RECT 227.430 595.720 229.350 596.770 ;
        RECT 230.190 595.720 232.110 596.770 ;
        RECT 232.950 595.720 234.870 596.770 ;
        RECT 235.710 595.720 237.630 596.770 ;
        RECT 238.470 595.720 240.390 596.770 ;
        RECT 241.230 595.720 243.150 596.770 ;
        RECT 243.990 595.720 245.910 596.770 ;
        RECT 246.750 595.720 248.670 596.770 ;
        RECT 249.510 595.720 251.430 596.770 ;
        RECT 252.270 595.720 254.190 596.770 ;
        RECT 255.030 595.720 256.950 596.770 ;
        RECT 257.790 595.720 259.710 596.770 ;
        RECT 260.550 595.720 262.470 596.770 ;
        RECT 263.310 595.720 265.230 596.770 ;
        RECT 266.070 595.720 267.990 596.770 ;
        RECT 268.830 595.720 270.750 596.770 ;
        RECT 271.590 595.720 273.510 596.770 ;
        RECT 274.350 595.720 276.270 596.770 ;
        RECT 277.110 595.720 279.030 596.770 ;
        RECT 279.870 595.720 281.790 596.770 ;
        RECT 282.630 595.720 284.550 596.770 ;
        RECT 285.390 595.720 299.830 596.770 ;
        RECT 4.230 4.280 299.830 595.720 ;
        RECT 4.230 3.670 11.310 4.280 ;
        RECT 12.150 3.670 16.830 4.280 ;
        RECT 17.670 3.670 22.350 4.280 ;
        RECT 23.190 3.670 27.870 4.280 ;
        RECT 28.710 3.670 33.390 4.280 ;
        RECT 34.230 3.670 38.910 4.280 ;
        RECT 39.750 3.670 44.430 4.280 ;
        RECT 45.270 3.670 49.950 4.280 ;
        RECT 50.790 3.670 55.470 4.280 ;
        RECT 56.310 3.670 60.990 4.280 ;
        RECT 61.830 3.670 66.510 4.280 ;
        RECT 67.350 3.670 72.030 4.280 ;
        RECT 72.870 3.670 77.550 4.280 ;
        RECT 78.390 3.670 83.070 4.280 ;
        RECT 83.910 3.670 88.590 4.280 ;
        RECT 89.430 3.670 94.110 4.280 ;
        RECT 94.950 3.670 99.630 4.280 ;
        RECT 100.470 3.670 105.150 4.280 ;
        RECT 105.990 3.670 110.670 4.280 ;
        RECT 111.510 3.670 116.190 4.280 ;
        RECT 117.030 3.670 121.710 4.280 ;
        RECT 122.550 3.670 127.230 4.280 ;
        RECT 128.070 3.670 132.750 4.280 ;
        RECT 133.590 3.670 138.270 4.280 ;
        RECT 139.110 3.670 143.790 4.280 ;
        RECT 144.630 3.670 149.310 4.280 ;
        RECT 150.150 3.670 154.830 4.280 ;
        RECT 155.670 3.670 160.350 4.280 ;
        RECT 161.190 3.670 165.870 4.280 ;
        RECT 166.710 3.670 171.390 4.280 ;
        RECT 172.230 3.670 176.910 4.280 ;
        RECT 177.750 3.670 182.430 4.280 ;
        RECT 183.270 3.670 187.950 4.280 ;
        RECT 188.790 3.670 193.470 4.280 ;
        RECT 194.310 3.670 198.990 4.280 ;
        RECT 199.830 3.670 204.510 4.280 ;
        RECT 205.350 3.670 210.030 4.280 ;
        RECT 210.870 3.670 215.550 4.280 ;
        RECT 216.390 3.670 221.070 4.280 ;
        RECT 221.910 3.670 226.590 4.280 ;
        RECT 227.430 3.670 232.110 4.280 ;
        RECT 232.950 3.670 237.630 4.280 ;
        RECT 238.470 3.670 243.150 4.280 ;
        RECT 243.990 3.670 248.670 4.280 ;
        RECT 249.510 3.670 254.190 4.280 ;
        RECT 255.030 3.670 259.710 4.280 ;
        RECT 260.550 3.670 265.230 4.280 ;
        RECT 266.070 3.670 270.750 4.280 ;
        RECT 271.590 3.670 276.270 4.280 ;
        RECT 277.110 3.670 281.790 4.280 ;
        RECT 282.630 3.670 287.310 4.280 ;
        RECT 288.150 3.670 299.830 4.280 ;
      LAYER met3 ;
        RECT 4.000 449.840 299.855 587.685 ;
        RECT 4.400 448.440 299.855 449.840 ;
        RECT 4.000 150.640 299.855 448.440 ;
        RECT 4.400 149.240 299.855 150.640 ;
        RECT 4.000 9.695 299.855 149.240 ;
      LAYER met4 ;
        RECT 11.335 11.055 20.640 583.945 ;
        RECT 23.040 11.055 97.440 583.945 ;
        RECT 99.840 11.055 174.240 583.945 ;
        RECT 176.640 11.055 251.040 583.945 ;
        RECT 253.440 11.055 297.785 583.945 ;
  END
END div_pipe_rasterizer_m
END LIBRARY

